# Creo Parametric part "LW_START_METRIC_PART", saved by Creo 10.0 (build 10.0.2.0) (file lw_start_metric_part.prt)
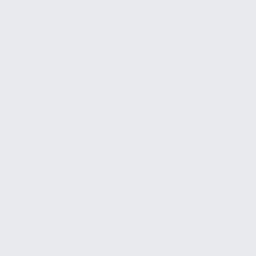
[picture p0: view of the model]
Units: hd_metric; MM, KILOGRAM, SECS
Materials in the file: DEFAULT

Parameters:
  DRW_UNITS = "METRIC"
  TOL_NAME = "MILLIMETERS"
  SUR = "6.3"
  LINEAR_TOL_0 = "1.0"
  PTC_WM_ITERATION = "0"
  PTC_WM_VERSION = "A.0"
  PTC_WM_LIFECYCLE_STATE = "Concept"
  PTC_WM_LIFECYCLE = "HD CAD Object"
  PTC_WM_LOCATION = "/Libraries/Library Templates/CAD/Parts"
  PTC_WM_CREATED_BY = "Graham, Jason (grahamj1: Harley-Davidson Motor Company)"
  PTC_WM_CREATED_ON = "18-Apr-22 02:46:01 PM"
  PTC_WM_MODIFIED_BY = "Graham, Jason (grahamj1: Harley-Davidson Motor Company)"
  PTC_WM_MODIFIED_ON = "18-Apr-22 02:46:02 PM"
  PTC_WM_NAME = "lw_start_metric_part.prt"
  PTC_WM_NUMBER = "LW_START_METRIC_PART.PRT"
  PTC_MASTER_MATERIAL = "DEFAULT"

Created from: HD_START_METRIC_PART.PRT

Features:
  1. datum plane "SIDE"
  2. datum plane "TOP"
  3. datum plane "FRONT"
  4. coordinate system
  5. datum point "PT_ORIG"

Other named items: CS_DEF, CONFIDENTIALITY_STATEMENT, COMB0001, CONFIDENTIALITY, ANNOT_LAYER_STATE0001, ANNOT_LAYER_STATE0002

Layers: ANNOT, AXES, COSMETIC, CS, CURVES, CURVES2, DATUMS, DEF_CS, DEF_DATUMS, PTS, SURFS

Notes: THIS CAD DOCUMENT AND ALL INFORMATION DISCLOSED HEREIN ARE THE EXCLUSIVE  | PROPERTY OF  | LIVEWIRE EV, LLC ("LIVEWIRE"), AND ARE SUBMITTED TO THE RECIPIENT  | ONLY ON A CONFIDENTIAL  | BASIS. IN CONSIDERATION OF RECEIVING THIS CAD DOCUMENT,  | THE RECIPIENT AGREES: (1) NOT TO  | USE THIS CAD DOCUMENT OR ANY OF THE INFORMATION DISCLOSED HEREIN TO PRODUCE ANY  | PRODUCT OR FOR ANY OTHER PURPOSE  | EXCEPT AS AUTHORIZED IN WRITING BY LIVEWIRE; (2) NOT TO  | REPRODUCE THIS CAD  | DOCUMENT; (3) TO RETURN THIS CAD DOCUMENT TO LIVEWIRE UPON REQUEST;  | AND (4)  | THAT NO DISCLOSURE OF THIS CAD DOCUMENT OR ANY OF THE INFORMATION DISCLOSED  | HEREIN WILL BE MADE TO ANY THIRD PARTY WITHOUT THE PRIOR WRITTEN CONSENT OF  | LIVEWIRE.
